VERSION 5.8 ;
DIVIDERCHAR "/" ;
BUSBITCHARS "[]" ;

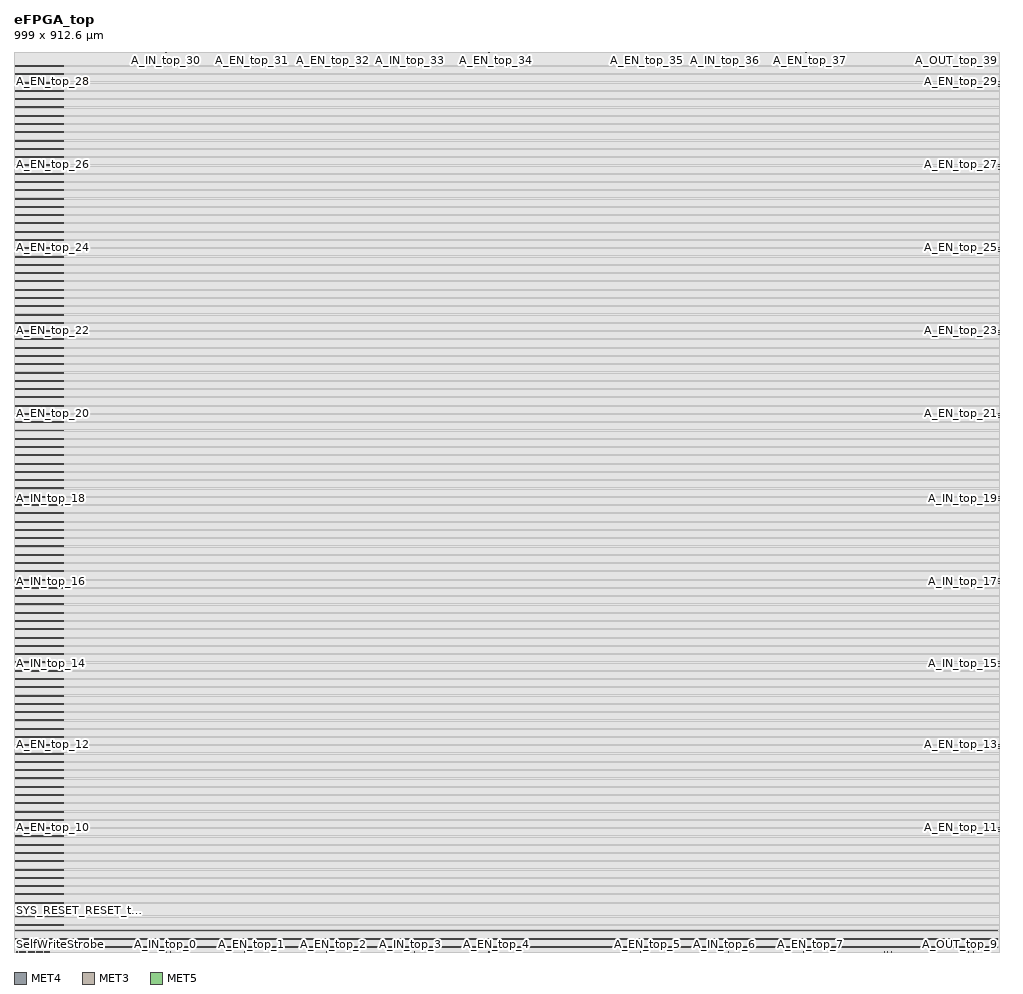
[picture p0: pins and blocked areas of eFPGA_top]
MACRO eFPGA_top
  CLASS BLOCK ;
  FOREIGN eFPGA_top ;
  ORIGIN 0.0 0.0 ;
  SIZE 999.000 BY 912.600 ;
  SYMMETRY X Y ;
  PIN CLK
    DIRECTION INPUT ;
    USE SIGNAL ;
    PORT
      LAYER MET4 ;
        RECT 2.450 0.000 2.550 0.550 ;
    END
  END CLK
  PIN A_EN_top_0
    DIRECTION OUTPUT ;
    USE SIGNAL ;
    PORT
      LAYER MET4 ;
        RECT 158.450 0.000 158.550 0.550 ;
    END
  END A_EN_top_0
  PIN A_EN_top_1
    DIRECTION OUTPUT ;
    USE SIGNAL ;
    PORT
      LAYER MET4 ;
        RECT 241.050 0.000 241.150 0.550 ;
    END
  END A_EN_top_1
  PIN A_EN_top_2
    DIRECTION OUTPUT ;
    USE SIGNAL ;
    PORT
      LAYER MET4 ;
        RECT 323.650 0.000 323.750 0.550 ;
    END
  END A_EN_top_2
  PIN A_EN_top_3
    DIRECTION OUTPUT ;
    USE SIGNAL ;
    PORT
      LAYER MET4 ;
        RECT 406.250 0.000 406.350 0.550 ;
    END
  END A_EN_top_3
  PIN A_EN_top_4
    DIRECTION OUTPUT ;
    USE SIGNAL ;
    PORT
      LAYER MET4 ;
        RECT 488.850 0.000 488.950 0.550 ;
    END
  END A_EN_top_4
  PIN A_EN_top_5
    DIRECTION OUTPUT ;
    USE SIGNAL ;
    PORT
      LAYER MET4 ;
        RECT 642.250 0.000 642.350 0.550 ;
    END
  END A_EN_top_5
  PIN A_EN_top_6
    DIRECTION OUTPUT ;
    USE SIGNAL ;
    PORT
      LAYER MET4 ;
        RECT 724.850 0.000 724.950 0.550 ;
    END
  END A_EN_top_6
  PIN A_EN_top_7
    DIRECTION OUTPUT ;
    USE SIGNAL ;
    PORT
      LAYER MET4 ;
        RECT 807.450 0.000 807.550 0.550 ;
    END
  END A_EN_top_7
  PIN A_EN_top_8
    DIRECTION OUTPUT ;
    USE SIGNAL ;
    PORT
      LAYER MET4 ;
        RECT 890.050 0.000 890.150 0.550 ;
    END
  END A_EN_top_8
  PIN A_EN_top_9
    DIRECTION OUTPUT ;
    USE SIGNAL ;
    PORT
      LAYER MET4 ;
        RECT 972.650 0.000 972.750 0.550 ;
    END
  END A_EN_top_9
  PIN A_EN_top_10
    DIRECTION OUTPUT ;
    USE SIGNAL ;
    PORT
      LAYER MET3 ;
        RECT 0.000 126.250 0.550 126.350 ;
    END
  END A_EN_top_10
  PIN A_EN_top_11
    DIRECTION OUTPUT ;
    USE SIGNAL ;
    PORT
      LAYER MET3 ;
        RECT 998.450 126.250 999.000 126.350 ;
    END
  END A_EN_top_11
  PIN A_EN_top_12
    DIRECTION OUTPUT ;
    USE SIGNAL ;
    PORT
      LAYER MET3 ;
        RECT 0.000 210.250 0.550 210.350 ;
    END
  END A_EN_top_12
  PIN A_EN_top_13
    DIRECTION OUTPUT ;
    USE SIGNAL ;
    PORT
      LAYER MET3 ;
        RECT 998.450 210.250 999.000 210.350 ;
    END
  END A_EN_top_13
  PIN A_EN_top_14
    DIRECTION OUTPUT ;
    USE SIGNAL ;
    PORT
      LAYER MET3 ;
        RECT 0.000 294.250 0.550 294.350 ;
    END
  END A_EN_top_14
  PIN A_EN_top_15
    DIRECTION OUTPUT ;
    USE SIGNAL ;
    PORT
      LAYER MET3 ;
        RECT 998.450 294.250 999.000 294.350 ;
    END
  END A_EN_top_15
  PIN A_EN_top_16
    DIRECTION OUTPUT ;
    USE SIGNAL ;
    PORT
      LAYER MET3 ;
        RECT 0.000 378.250 0.550 378.350 ;
    END
  END A_EN_top_16
  PIN A_EN_top_17
    DIRECTION OUTPUT ;
    USE SIGNAL ;
    PORT
      LAYER MET3 ;
        RECT 998.450 378.250 999.000 378.350 ;
    END
  END A_EN_top_17
  PIN A_EN_top_18
    DIRECTION OUTPUT ;
    USE SIGNAL ;
    PORT
      LAYER MET3 ;
        RECT 0.000 462.250 0.550 462.350 ;
    END
  END A_EN_top_18
  PIN A_EN_top_19
    DIRECTION OUTPUT ;
    USE SIGNAL ;
    PORT
      LAYER MET3 ;
        RECT 998.450 462.250 999.000 462.350 ;
    END
  END A_EN_top_19
  PIN A_EN_top_20
    DIRECTION OUTPUT ;
    USE SIGNAL ;
    PORT
      LAYER MET3 ;
        RECT 0.000 546.250 0.550 546.350 ;
    END
  END A_EN_top_20
  PIN A_EN_top_21
    DIRECTION OUTPUT ;
    USE SIGNAL ;
    PORT
      LAYER MET3 ;
        RECT 998.450 546.250 999.000 546.350 ;
    END
  END A_EN_top_21
  PIN A_EN_top_22
    DIRECTION OUTPUT ;
    USE SIGNAL ;
    PORT
      LAYER MET3 ;
        RECT 0.000 630.250 0.550 630.350 ;
    END
  END A_EN_top_22
  PIN A_EN_top_23
    DIRECTION OUTPUT ;
    USE SIGNAL ;
    PORT
      LAYER MET3 ;
        RECT 998.450 630.250 999.000 630.350 ;
    END
  END A_EN_top_23
  PIN A_EN_top_24
    DIRECTION OUTPUT ;
    USE SIGNAL ;
    PORT
      LAYER MET3 ;
        RECT 0.000 714.250 0.550 714.350 ;
    END
  END A_EN_top_24
  PIN A_EN_top_25
    DIRECTION OUTPUT ;
    USE SIGNAL ;
    PORT
      LAYER MET3 ;
        RECT 998.450 714.250 999.000 714.350 ;
    END
  END A_EN_top_25
  PIN A_EN_top_26
    DIRECTION OUTPUT ;
    USE SIGNAL ;
    PORT
      LAYER MET3 ;
        RECT 0.000 798.250 0.550 798.350 ;
    END
  END A_EN_top_26
  PIN A_EN_top_27
    DIRECTION OUTPUT ;
    USE SIGNAL ;
    PORT
      LAYER MET3 ;
        RECT 998.450 798.250 999.000 798.350 ;
    END
  END A_EN_top_27
  PIN A_EN_top_28
    DIRECTION OUTPUT ;
    USE SIGNAL ;
    PORT
      LAYER MET3 ;
        RECT 0.000 882.250 0.550 882.350 ;
    END
  END A_EN_top_28
  PIN A_EN_top_29
    DIRECTION OUTPUT ;
    USE SIGNAL ;
    PORT
      LAYER MET3 ;
        RECT 998.450 882.250 999.000 882.350 ;
    END
  END A_EN_top_29
  PIN A_EN_top_30
    DIRECTION OUTPUT ;
    USE SIGNAL ;
    PORT
      LAYER MET4 ;
        RECT 158.450 912.050 158.550 912.600 ;
    END
  END A_EN_top_30
  PIN A_EN_top_31
    DIRECTION OUTPUT ;
    USE SIGNAL ;
    PORT
      LAYER MET4 ;
        RECT 241.050 912.050 241.150 912.600 ;
    END
  END A_EN_top_31
  PIN A_EN_top_32
    DIRECTION OUTPUT ;
    USE SIGNAL ;
    PORT
      LAYER MET4 ;
        RECT 323.650 912.050 323.750 912.600 ;
    END
  END A_EN_top_32
  PIN A_EN_top_33
    DIRECTION OUTPUT ;
    USE SIGNAL ;
    PORT
      LAYER MET4 ;
        RECT 406.250 912.050 406.350 912.600 ;
    END
  END A_EN_top_33
  PIN A_EN_top_34
    DIRECTION OUTPUT ;
    USE SIGNAL ;
    PORT
      LAYER MET4 ;
        RECT 488.850 912.050 488.950 912.600 ;
    END
  END A_EN_top_34
  PIN A_EN_top_35
    DIRECTION OUTPUT ;
    USE SIGNAL ;
    PORT
      LAYER MET4 ;
        RECT 642.250 912.050 642.350 912.600 ;
    END
  END A_EN_top_35
  PIN A_EN_top_36
    DIRECTION OUTPUT ;
    USE SIGNAL ;
    PORT
      LAYER MET4 ;
        RECT 724.850 912.050 724.950 912.600 ;
    END
  END A_EN_top_36
  PIN A_EN_top_37
    DIRECTION OUTPUT ;
    USE SIGNAL ;
    PORT
      LAYER MET4 ;
        RECT 807.450 912.050 807.550 912.600 ;
    END
  END A_EN_top_37
  PIN A_EN_top_38
    DIRECTION OUTPUT ;
    USE SIGNAL ;
    PORT
      LAYER MET4 ;
        RECT 890.050 912.050 890.150 912.600 ;
    END
  END A_EN_top_38
  PIN A_EN_top_39
    DIRECTION OUTPUT ;
    USE SIGNAL ;
    PORT
      LAYER MET4 ;
        RECT 972.650 912.050 972.750 912.600 ;
    END
  END A_EN_top_39
  PIN A_IN_top_0
    DIRECTION OUTPUT ;
    USE SIGNAL ;
    PORT
      LAYER MET4 ;
        RECT 154.050 0.000 154.150 0.550 ;
    END
  END A_IN_top_0
  PIN A_IN_top_1
    DIRECTION OUTPUT ;
    USE SIGNAL ;
    PORT
      LAYER MET4 ;
        RECT 236.650 0.000 236.750 0.550 ;
    END
  END A_IN_top_1
  PIN A_IN_top_2
    DIRECTION OUTPUT ;
    USE SIGNAL ;
    PORT
      LAYER MET4 ;
        RECT 319.250 0.000 319.350 0.550 ;
    END
  END A_IN_top_2
  PIN A_IN_top_3
    DIRECTION OUTPUT ;
    USE SIGNAL ;
    PORT
      LAYER MET4 ;
        RECT 401.850 0.000 401.950 0.550 ;
    END
  END A_IN_top_3
  PIN A_IN_top_4
    DIRECTION OUTPUT ;
    USE SIGNAL ;
    PORT
      LAYER MET4 ;
        RECT 484.450 0.000 484.550 0.550 ;
    END
  END A_IN_top_4
  PIN A_IN_top_5
    DIRECTION OUTPUT ;
    USE SIGNAL ;
    PORT
      LAYER MET4 ;
        RECT 637.850 0.000 637.950 0.550 ;
    END
  END A_IN_top_5
  PIN A_IN_top_6
    DIRECTION OUTPUT ;
    USE SIGNAL ;
    PORT
      LAYER MET4 ;
        RECT 720.450 0.000 720.550 0.550 ;
    END
  END A_IN_top_6
  PIN A_IN_top_7
    DIRECTION OUTPUT ;
    USE SIGNAL ;
    PORT
      LAYER MET4 ;
        RECT 803.050 0.000 803.150 0.550 ;
    END
  END A_IN_top_7
  PIN A_IN_top_8
    DIRECTION OUTPUT ;
    USE SIGNAL ;
    PORT
      LAYER MET4 ;
        RECT 885.650 0.000 885.750 0.550 ;
    END
  END A_IN_top_8
  PIN A_IN_top_9
    DIRECTION OUTPUT ;
    USE SIGNAL ;
    PORT
      LAYER MET4 ;
        RECT 968.250 0.000 968.350 0.550 ;
    END
  END A_IN_top_9
  PIN A_IN_top_10
    DIRECTION OUTPUT ;
    USE SIGNAL ;
    PORT
      LAYER MET3 ;
        RECT 0.000 124.050 0.550 124.150 ;
    END
  END A_IN_top_10
  PIN A_IN_top_11
    DIRECTION OUTPUT ;
    USE SIGNAL ;
    PORT
      LAYER MET3 ;
        RECT 998.450 124.050 999.000 124.150 ;
    END
  END A_IN_top_11
  PIN A_IN_top_12
    DIRECTION OUTPUT ;
    USE SIGNAL ;
    PORT
      LAYER MET3 ;
        RECT 0.000 208.050 0.550 208.150 ;
    END
  END A_IN_top_12
  PIN A_IN_top_13
    DIRECTION OUTPUT ;
    USE SIGNAL ;
    PORT
      LAYER MET3 ;
        RECT 998.450 208.050 999.000 208.150 ;
    END
  END A_IN_top_13
  PIN A_IN_top_14
    DIRECTION OUTPUT ;
    USE SIGNAL ;
    PORT
      LAYER MET3 ;
        RECT 0.000 292.050 0.550 292.150 ;
    END
  END A_IN_top_14
  PIN A_IN_top_15
    DIRECTION OUTPUT ;
    USE SIGNAL ;
    PORT
      LAYER MET3 ;
        RECT 998.450 292.050 999.000 292.150 ;
    END
  END A_IN_top_15
  PIN A_IN_top_16
    DIRECTION OUTPUT ;
    USE SIGNAL ;
    PORT
      LAYER MET3 ;
        RECT 0.000 376.050 0.550 376.150 ;
    END
  END A_IN_top_16
  PIN A_IN_top_17
    DIRECTION OUTPUT ;
    USE SIGNAL ;
    PORT
      LAYER MET3 ;
        RECT 998.450 376.050 999.000 376.150 ;
    END
  END A_IN_top_17
  PIN A_IN_top_18
    DIRECTION OUTPUT ;
    USE SIGNAL ;
    PORT
      LAYER MET3 ;
        RECT 0.000 460.050 0.550 460.150 ;
    END
  END A_IN_top_18
  PIN A_IN_top_19
    DIRECTION OUTPUT ;
    USE SIGNAL ;
    PORT
      LAYER MET3 ;
        RECT 998.450 460.050 999.000 460.150 ;
    END
  END A_IN_top_19
  PIN A_IN_top_20
    DIRECTION OUTPUT ;
    USE SIGNAL ;
    PORT
      LAYER MET3 ;
        RECT 0.000 544.050 0.550 544.150 ;
    END
  END A_IN_top_20
  PIN A_IN_top_21
    DIRECTION OUTPUT ;
    USE SIGNAL ;
    PORT
      LAYER MET3 ;
        RECT 998.450 544.050 999.000 544.150 ;
    END
  END A_IN_top_21
  PIN A_IN_top_22
    DIRECTION OUTPUT ;
    USE SIGNAL ;
    PORT
      LAYER MET3 ;
        RECT 0.000 628.050 0.550 628.150 ;
    END
  END A_IN_top_22
  PIN A_IN_top_23
    DIRECTION OUTPUT ;
    USE SIGNAL ;
    PORT
      LAYER MET3 ;
        RECT 998.450 628.050 999.000 628.150 ;
    END
  END A_IN_top_23
  PIN A_IN_top_24
    DIRECTION OUTPUT ;
    USE SIGNAL ;
    PORT
      LAYER MET3 ;
        RECT 0.000 712.050 0.550 712.150 ;
    END
  END A_IN_top_24
  PIN A_IN_top_25
    DIRECTION OUTPUT ;
    USE SIGNAL ;
    PORT
      LAYER MET3 ;
        RECT 998.450 712.050 999.000 712.150 ;
    END
  END A_IN_top_25
  PIN A_IN_top_26
    DIRECTION OUTPUT ;
    USE SIGNAL ;
    PORT
      LAYER MET3 ;
        RECT 0.000 796.050 0.550 796.150 ;
    END
  END A_IN_top_26
  PIN A_IN_top_27
    DIRECTION OUTPUT ;
    USE SIGNAL ;
    PORT
      LAYER MET3 ;
        RECT 998.450 796.050 999.000 796.150 ;
    END
  END A_IN_top_27
  PIN A_IN_top_28
    DIRECTION OUTPUT ;
    USE SIGNAL ;
    PORT
      LAYER MET3 ;
        RECT 0.000 880.050 0.550 880.150 ;
    END
  END A_IN_top_28
  PIN A_IN_top_29
    DIRECTION OUTPUT ;
    USE SIGNAL ;
    PORT
      LAYER MET3 ;
        RECT 998.450 880.050 999.000 880.150 ;
    END
  END A_IN_top_29
  PIN A_IN_top_30
    DIRECTION OUTPUT ;
    USE SIGNAL ;
    PORT
      LAYER MET4 ;
        RECT 154.050 912.050 154.150 912.600 ;
    END
  END A_IN_top_30
  PIN A_IN_top_31
    DIRECTION OUTPUT ;
    USE SIGNAL ;
    PORT
      LAYER MET4 ;
        RECT 236.650 912.050 236.750 912.600 ;
    END
  END A_IN_top_31
  PIN A_IN_top_32
    DIRECTION OUTPUT ;
    USE SIGNAL ;
    PORT
      LAYER MET4 ;
        RECT 319.250 912.050 319.350 912.600 ;
    END
  END A_IN_top_32
  PIN A_IN_top_33
    DIRECTION OUTPUT ;
    USE SIGNAL ;
    PORT
      LAYER MET4 ;
        RECT 401.850 912.050 401.950 912.600 ;
    END
  END A_IN_top_33
  PIN A_IN_top_34
    DIRECTION OUTPUT ;
    USE SIGNAL ;
    PORT
      LAYER MET4 ;
        RECT 484.450 912.050 484.550 912.600 ;
    END
  END A_IN_top_34
  PIN A_IN_top_35
    DIRECTION OUTPUT ;
    USE SIGNAL ;
    PORT
      LAYER MET4 ;
        RECT 637.850 912.050 637.950 912.600 ;
    END
  END A_IN_top_35
  PIN A_IN_top_36
    DIRECTION OUTPUT ;
    USE SIGNAL ;
    PORT
      LAYER MET4 ;
        RECT 720.450 912.050 720.550 912.600 ;
    END
  END A_IN_top_36
  PIN A_IN_top_37
    DIRECTION OUTPUT ;
    USE SIGNAL ;
    PORT
      LAYER MET4 ;
        RECT 803.050 912.050 803.150 912.600 ;
    END
  END A_IN_top_37
  PIN A_IN_top_38
    DIRECTION OUTPUT ;
    USE SIGNAL ;
    PORT
      LAYER MET4 ;
        RECT 885.650 912.050 885.750 912.600 ;
    END
  END A_IN_top_38
  PIN A_IN_top_39
    DIRECTION OUTPUT ;
    USE SIGNAL ;
    PORT
      LAYER MET4 ;
        RECT 968.250 912.050 968.350 912.600 ;
    END
  END A_IN_top_39
  PIN A_OUT_top_0
    DIRECTION INPUT ;
    USE SIGNAL ;
    PORT
      LAYER MET4 ;
        RECT 151.250 0.000 151.350 0.550 ;
    END
  END A_OUT_top_0
  PIN A_OUT_top_1
    DIRECTION INPUT ;
    USE SIGNAL ;
    PORT
      LAYER MET4 ;
        RECT 233.850 0.000 233.950 0.550 ;
    END
  END A_OUT_top_1
  PIN A_OUT_top_2
    DIRECTION INPUT ;
    USE SIGNAL ;
    PORT
      LAYER MET4 ;
        RECT 316.450 0.000 316.550 0.550 ;
    END
  END A_OUT_top_2
  PIN A_OUT_top_3
    DIRECTION INPUT ;
    USE SIGNAL ;
    PORT
      LAYER MET4 ;
        RECT 399.050 0.000 399.150 0.550 ;
    END
  END A_OUT_top_3
  PIN A_OUT_top_4
    DIRECTION INPUT ;
    USE SIGNAL ;
    PORT
      LAYER MET4 ;
        RECT 481.650 0.000 481.750 0.550 ;
    END
  END A_OUT_top_4
  PIN A_OUT_top_5
    DIRECTION INPUT ;
    USE SIGNAL ;
    PORT
      LAYER MET4 ;
        RECT 635.050 0.000 635.150 0.550 ;
    END
  END A_OUT_top_5
  PIN A_OUT_top_6
    DIRECTION INPUT ;
    USE SIGNAL ;
    PORT
      LAYER MET4 ;
        RECT 717.650 0.000 717.750 0.550 ;
    END
  END A_OUT_top_6
  PIN A_OUT_top_7
    DIRECTION INPUT ;
    USE SIGNAL ;
    PORT
      LAYER MET4 ;
        RECT 800.250 0.000 800.350 0.550 ;
    END
  END A_OUT_top_7
  PIN A_OUT_top_8
    DIRECTION INPUT ;
    USE SIGNAL ;
    PORT
      LAYER MET4 ;
        RECT 882.850 0.000 882.950 0.550 ;
    END
  END A_OUT_top_8
  PIN A_OUT_top_9
    DIRECTION INPUT ;
    USE SIGNAL ;
    PORT
      LAYER MET4 ;
        RECT 965.450 0.000 965.550 0.550 ;
    END
  END A_OUT_top_9
  PIN A_OUT_top_10
    DIRECTION INPUT ;
    USE SIGNAL ;
    PORT
      LAYER MET3 ;
        RECT 0.000 121.850 0.550 121.950 ;
    END
  END A_OUT_top_10
  PIN A_OUT_top_11
    DIRECTION INPUT ;
    USE SIGNAL ;
    PORT
      LAYER MET3 ;
        RECT 998.450 121.850 999.000 121.950 ;
    END
  END A_OUT_top_11
  PIN A_OUT_top_12
    DIRECTION INPUT ;
    USE SIGNAL ;
    PORT
      LAYER MET3 ;
        RECT 0.000 205.850 0.550 205.950 ;
    END
  END A_OUT_top_12
  PIN A_OUT_top_13
    DIRECTION INPUT ;
    USE SIGNAL ;
    PORT
      LAYER MET3 ;
        RECT 998.450 205.850 999.000 205.950 ;
    END
  END A_OUT_top_13
  PIN A_OUT_top_14
    DIRECTION INPUT ;
    USE SIGNAL ;
    PORT
      LAYER MET3 ;
        RECT 0.000 289.850 0.550 289.950 ;
    END
  END A_OUT_top_14
  PIN A_OUT_top_15
    DIRECTION INPUT ;
    USE SIGNAL ;
    PORT
      LAYER MET3 ;
        RECT 998.450 289.850 999.000 289.950 ;
    END
  END A_OUT_top_15
  PIN A_OUT_top_16
    DIRECTION INPUT ;
    USE SIGNAL ;
    PORT
      LAYER MET3 ;
        RECT 0.000 373.850 0.550 373.950 ;
    END
  END A_OUT_top_16
  PIN A_OUT_top_17
    DIRECTION INPUT ;
    USE SIGNAL ;
    PORT
      LAYER MET3 ;
        RECT 998.450 373.850 999.000 373.950 ;
    END
  END A_OUT_top_17
  PIN A_OUT_top_18
    DIRECTION INPUT ;
    USE SIGNAL ;
    PORT
      LAYER MET3 ;
        RECT 0.000 457.850 0.550 457.950 ;
    END
  END A_OUT_top_18
  PIN A_OUT_top_19
    DIRECTION INPUT ;
    USE SIGNAL ;
    PORT
      LAYER MET3 ;
        RECT 998.450 457.850 999.000 457.950 ;
    END
  END A_OUT_top_19
  PIN A_OUT_top_20
    DIRECTION INPUT ;
    USE SIGNAL ;
    PORT
      LAYER MET3 ;
        RECT 0.000 541.850 0.550 541.950 ;
    END
  END A_OUT_top_20
  PIN A_OUT_top_21
    DIRECTION INPUT ;
    USE SIGNAL ;
    PORT
      LAYER MET3 ;
        RECT 998.450 541.850 999.000 541.950 ;
    END
  END A_OUT_top_21
  PIN A_OUT_top_22
    DIRECTION INPUT ;
    USE SIGNAL ;
    PORT
      LAYER MET3 ;
        RECT 0.000 625.850 0.550 625.950 ;
    END
  END A_OUT_top_22
  PIN A_OUT_top_23
    DIRECTION INPUT ;
    USE SIGNAL ;
    PORT
      LAYER MET3 ;
        RECT 998.450 625.850 999.000 625.950 ;
    END
  END A_OUT_top_23
  PIN A_OUT_top_24
    DIRECTION INPUT ;
    USE SIGNAL ;
    PORT
      LAYER MET3 ;
        RECT 0.000 709.850 0.550 709.950 ;
    END
  END A_OUT_top_24
  PIN A_OUT_top_25
    DIRECTION INPUT ;
    USE SIGNAL ;
    PORT
      LAYER MET3 ;
        RECT 998.450 709.850 999.000 709.950 ;
    END
  END A_OUT_top_25
  PIN A_OUT_top_26
    DIRECTION INPUT ;
    USE SIGNAL ;
    PORT
      LAYER MET3 ;
        RECT 0.000 793.850 0.550 793.950 ;
    END
  END A_OUT_top_26
  PIN A_OUT_top_27
    DIRECTION INPUT ;
    USE SIGNAL ;
    PORT
      LAYER MET3 ;
        RECT 998.450 793.850 999.000 793.950 ;
    END
  END A_OUT_top_27
  PIN A_OUT_top_28
    DIRECTION INPUT ;
    USE SIGNAL ;
    PORT
      LAYER MET3 ;
        RECT 0.000 877.850 0.550 877.950 ;
    END
  END A_OUT_top_28
  PIN A_OUT_top_29
    DIRECTION INPUT ;
    USE SIGNAL ;
    PORT
      LAYER MET3 ;
        RECT 998.450 877.850 999.000 877.950 ;
    END
  END A_OUT_top_29
  PIN A_OUT_top_30
    DIRECTION INPUT ;
    USE SIGNAL ;
    PORT
      LAYER MET4 ;
        RECT 151.250 912.050 151.350 912.600 ;
    END
  END A_OUT_top_30
  PIN A_OUT_top_31
    DIRECTION INPUT ;
    USE SIGNAL ;
    PORT
      LAYER MET4 ;
        RECT 233.850 912.050 233.950 912.600 ;
    END
  END A_OUT_top_31
  PIN A_OUT_top_32
    DIRECTION INPUT ;
    USE SIGNAL ;
    PORT
      LAYER MET4 ;
        RECT 316.450 912.050 316.550 912.600 ;
    END
  END A_OUT_top_32
  PIN A_OUT_top_33
    DIRECTION INPUT ;
    USE SIGNAL ;
    PORT
      LAYER MET4 ;
        RECT 399.050 912.050 399.150 912.600 ;
    END
  END A_OUT_top_33
  PIN A_OUT_top_34
    DIRECTION INPUT ;
    USE SIGNAL ;
    PORT
      LAYER MET4 ;
        RECT 481.650 912.050 481.750 912.600 ;
    END
  END A_OUT_top_34
  PIN A_OUT_top_35
    DIRECTION INPUT ;
    USE SIGNAL ;
    PORT
      LAYER MET4 ;
        RECT 635.050 912.050 635.150 912.600 ;
    END
  END A_OUT_top_35
  PIN A_OUT_top_36
    DIRECTION INPUT ;
    USE SIGNAL ;
    PORT
      LAYER MET4 ;
        RECT 717.650 912.050 717.750 912.600 ;
    END
  END A_OUT_top_36
  PIN A_OUT_top_37
    DIRECTION INPUT ;
    USE SIGNAL ;
    PORT
      LAYER MET4 ;
        RECT 800.250 912.050 800.350 912.600 ;
    END
  END A_OUT_top_37
  PIN A_OUT_top_38
    DIRECTION INPUT ;
    USE SIGNAL ;
    PORT
      LAYER MET4 ;
        RECT 882.850 912.050 882.950 912.600 ;
    END
  END A_OUT_top_38
  PIN A_OUT_top_39
    DIRECTION INPUT ;
    USE SIGNAL ;
    PORT
      LAYER MET4 ;
        RECT 965.450 912.050 965.550 912.600 ;
    END
  END A_OUT_top_39
  PIN SYS_RESET_RESET_top
    DIRECTION INPUT ;
    USE SIGNAL ;
    PORT
      LAYER MET3 ;
        RECT 0.000 42.050 0.550 42.150 ;
    END
  END SYS_RESET_RESET_top
  PIN resetn
    DIRECTION INPUT ;
    USE SIGNAL ;
    PORT
      LAYER MET4 ;
        RECT 33.050 0.000 33.150 0.550 ;
    END
  END resetn
  PIN Rx
    DIRECTION INPUT ;
    USE SIGNAL ;
    PORT
      LAYER MET4 ;
        RECT 7.250 0.000 7.350 0.550 ;
    END
  END Rx
  PIN ComActive
    DIRECTION OUTPUT ;
    USE SIGNAL ;
    PORT
      LAYER MET4 ;
        RECT 3.050 0.000 3.150 0.550 ;
    END
  END ComActive
  PIN ReceiveLED
    DIRECTION OUTPUT ;
    USE SIGNAL ;
    PORT
      LAYER MET4 ;
        RECT 6.650 0.000 6.750 0.550 ;
    END
  END ReceiveLED
  PIN s_clk
    DIRECTION INPUT ;
    USE SIGNAL ;
    PORT
      LAYER MET4 ;
        RECT 33.650 0.000 33.750 0.550 ;
    END
  END s_clk
  PIN s_data
    DIRECTION INPUT ;
    USE SIGNAL ;
    PORT
      LAYER MET4 ;
        RECT 34.250 0.000 34.350 0.550 ;
    END
  END s_data
  PIN spi_sck
    DIRECTION INPUT ;
    USE SIGNAL ;
    PORT
      LAYER MET4 ;
        RECT 36.050 0.000 36.150 0.550 ;
    END
  END spi_sck
  PIN spi_cs_n
    DIRECTION INPUT ;
    USE SIGNAL ;
    PORT
      LAYER MET4 ;
        RECT 34.850 0.000 34.950 0.550 ;
    END
  END spi_cs_n
  PIN spi_mosi
    DIRECTION INPUT ;
    USE SIGNAL ;
    PORT
      LAYER MET4 ;
        RECT 35.450 0.000 35.550 0.550 ;
    END
  END spi_mosi
  PIN SelfWriteData_0
    DIRECTION INPUT ;
    USE SIGNAL ;
    PORT
      LAYER MET4 ;
        RECT 7.850 0.000 7.950 0.550 ;
    END
  END SelfWriteData_0
  PIN SelfWriteData_1
    DIRECTION INPUT ;
    USE SIGNAL ;
    PORT
      LAYER MET4 ;
        RECT 8.450 0.000 8.550 0.550 ;
    END
  END SelfWriteData_1
  PIN SelfWriteData_2
    DIRECTION INPUT ;
    USE SIGNAL ;
    PORT
      LAYER MET4 ;
        RECT 16.850 0.000 16.950 0.550 ;
    END
  END SelfWriteData_2
  PIN SelfWriteData_3
    DIRECTION INPUT ;
    USE SIGNAL ;
    PORT
      LAYER MET4 ;
        RECT 25.250 0.000 25.350 0.550 ;
    END
  END SelfWriteData_3
  PIN SelfWriteData_4
    DIRECTION INPUT ;
    USE SIGNAL ;
    PORT
      LAYER MET4 ;
        RECT 27.050 0.000 27.150 0.550 ;
    END
  END SelfWriteData_4
  PIN SelfWriteData_5
    DIRECTION INPUT ;
    USE SIGNAL ;
    PORT
      LAYER MET4 ;
        RECT 27.650 0.000 27.750 0.550 ;
    END
  END SelfWriteData_5
  PIN SelfWriteData_6
    DIRECTION INPUT ;
    USE SIGNAL ;
    PORT
      LAYER MET4 ;
        RECT 28.250 0.000 28.350 0.550 ;
    END
  END SelfWriteData_6
  PIN SelfWriteData_7
    DIRECTION INPUT ;
    USE SIGNAL ;
    PORT
      LAYER MET4 ;
        RECT 28.850 0.000 28.950 0.550 ;
    END
  END SelfWriteData_7
  PIN SelfWriteData_8
    DIRECTION INPUT ;
    USE SIGNAL ;
    PORT
      LAYER MET4 ;
        RECT 31.250 0.000 31.350 0.550 ;
    END
  END SelfWriteData_8
  PIN SelfWriteData_9
    DIRECTION INPUT ;
    USE SIGNAL ;
    PORT
      LAYER MET4 ;
        RECT 31.850 0.000 31.950 0.550 ;
    END
  END SelfWriteData_9
  PIN SelfWriteData_10
    DIRECTION INPUT ;
    USE SIGNAL ;
    PORT
      LAYER MET4 ;
        RECT 9.050 0.000 9.150 0.550 ;
    END
  END SelfWriteData_10
  PIN SelfWriteData_11
    DIRECTION INPUT ;
    USE SIGNAL ;
    PORT
      LAYER MET4 ;
        RECT 9.650 0.000 9.750 0.550 ;
    END
  END SelfWriteData_11
  PIN SelfWriteData_12
    DIRECTION INPUT ;
    USE SIGNAL ;
    PORT
      LAYER MET4 ;
        RECT 10.250 0.000 10.350 0.550 ;
    END
  END SelfWriteData_12
  PIN SelfWriteData_13
    DIRECTION INPUT ;
    USE SIGNAL ;
    PORT
      LAYER MET4 ;
        RECT 10.850 0.000 10.950 0.550 ;
    END
  END SelfWriteData_13
  PIN SelfWriteData_14
    DIRECTION INPUT ;
    USE SIGNAL ;
    PORT
      LAYER MET4 ;
        RECT 11.450 0.000 11.550 0.550 ;
    END
  END SelfWriteData_14
  PIN SelfWriteData_15
    DIRECTION INPUT ;
    USE SIGNAL ;
    PORT
      LAYER MET4 ;
        RECT 12.050 0.000 12.150 0.550 ;
    END
  END SelfWriteData_15
  PIN SelfWriteData_16
    DIRECTION INPUT ;
    USE SIGNAL ;
    PORT
      LAYER MET4 ;
        RECT 14.450 0.000 14.550 0.550 ;
    END
  END SelfWriteData_16
  PIN SelfWriteData_17
    DIRECTION INPUT ;
    USE SIGNAL ;
    PORT
      LAYER MET4 ;
        RECT 15.050 0.000 15.150 0.550 ;
    END
  END SelfWriteData_17
  PIN SelfWriteData_18
    DIRECTION INPUT ;
    USE SIGNAL ;
    PORT
      LAYER MET4 ;
        RECT 15.650 0.000 15.750 0.550 ;
    END
  END SelfWriteData_18
  PIN SelfWriteData_19
    DIRECTION INPUT ;
    USE SIGNAL ;
    PORT
      LAYER MET4 ;
        RECT 16.250 0.000 16.350 0.550 ;
    END
  END SelfWriteData_19
  PIN SelfWriteData_20
    DIRECTION INPUT ;
    USE SIGNAL ;
    PORT
      LAYER MET4 ;
        RECT 17.450 0.000 17.550 0.550 ;
    END
  END SelfWriteData_20
  PIN SelfWriteData_21
    DIRECTION INPUT ;
    USE SIGNAL ;
    PORT
      LAYER MET4 ;
        RECT 18.050 0.000 18.150 0.550 ;
    END
  END SelfWriteData_21
  PIN SelfWriteData_22
    DIRECTION INPUT ;
    USE SIGNAL ;
    PORT
      LAYER MET4 ;
        RECT 18.650 0.000 18.750 0.550 ;
    END
  END SelfWriteData_22
  PIN SelfWriteData_23
    DIRECTION INPUT ;
    USE SIGNAL ;
    PORT
      LAYER MET4 ;
        RECT 19.250 0.000 19.350 0.550 ;
    END
  END SelfWriteData_23
  PIN SelfWriteData_24
    DIRECTION INPUT ;
    USE SIGNAL ;
    PORT
      LAYER MET4 ;
        RECT 19.850 0.000 19.950 0.550 ;
    END
  END SelfWriteData_24
  PIN SelfWriteData_25
    DIRECTION INPUT ;
    USE SIGNAL ;
    PORT
      LAYER MET4 ;
        RECT 20.450 0.000 20.550 0.550 ;
    END
  END SelfWriteData_25
  PIN SelfWriteData_26
    DIRECTION INPUT ;
    USE SIGNAL ;
    PORT
      LAYER MET4 ;
        RECT 22.850 0.000 22.950 0.550 ;
    END
  END SelfWriteData_26
  PIN SelfWriteData_27
    DIRECTION INPUT ;
    USE SIGNAL ;
    PORT
      LAYER MET4 ;
        RECT 23.450 0.000 23.550 0.550 ;
    END
  END SelfWriteData_27
  PIN SelfWriteData_28
    DIRECTION INPUT ;
    USE SIGNAL ;
    PORT
      LAYER MET4 ;
        RECT 24.050 0.000 24.150 0.550 ;
    END
  END SelfWriteData_28
  PIN SelfWriteData_29
    DIRECTION INPUT ;
    USE SIGNAL ;
    PORT
      LAYER MET4 ;
        RECT 24.650 0.000 24.750 0.550 ;
    END
  END SelfWriteData_29
  PIN SelfWriteData_30
    DIRECTION INPUT ;
    USE SIGNAL ;
    PORT
      LAYER MET4 ;
        RECT 25.850 0.000 25.950 0.550 ;
    END
  END SelfWriteData_30
  PIN SelfWriteData_31
    DIRECTION INPUT ;
    USE SIGNAL ;
    PORT
      LAYER MET4 ;
        RECT 26.450 0.000 26.550 0.550 ;
    END
  END SelfWriteData_31
  PIN SelfWriteStrobe
    DIRECTION INPUT ;
    USE SIGNAL ;
    PORT
      LAYER MET4 ;
        RECT 32.450 0.000 32.550 0.550 ;
    END
  END SelfWriteStrobe
  PIN ConfigBusy
    DIRECTION OUTPUT ;
    USE SIGNAL ;
    PORT
      LAYER MET4 ;
        RECT 3.650 0.000 3.750 0.550 ;
    END
  END ConfigBusy
  PIN Configured
    DIRECTION OUTPUT ;
    USE SIGNAL ;
    PORT
      LAYER MET4 ;
        RECT 6.050 0.000 6.150 0.550 ;
    END
  END Configured
  PIN vdd_stripe_generate
    DIRECTION INOUT ;
    USE POWER ;
    PORT
      LAYER MET5 ;
        RECT 2.000 889.500 50.000 890.500 ;
      LAYER MET5 ;
        RECT 2.000 805.500 50.000 806.500 ;
      LAYER MET5 ;
        RECT 2.000 822.300 50.000 823.300 ;
      LAYER MET5 ;
        RECT 2.000 839.100 50.000 840.100 ;
      LAYER MET5 ;
        RECT 2.000 855.900 50.000 856.900 ;
      LAYER MET5 ;
        RECT 2.000 872.700 50.000 873.700 ;
      LAYER MET5 ;
        RECT 2.000 721.500 50.000 722.500 ;
      LAYER MET5 ;
        RECT 2.000 738.300 50.000 739.300 ;
      LAYER MET5 ;
        RECT 2.000 755.100 50.000 756.100 ;
      LAYER MET5 ;
        RECT 2.000 771.900 50.000 772.900 ;
      LAYER MET5 ;
        RECT 2.000 788.700 50.000 789.700 ;
      LAYER MET5 ;
        RECT 2.000 637.500 50.000 638.500 ;
      LAYER MET5 ;
        RECT 2.000 654.300 50.000 655.300 ;
      LAYER MET5 ;
        RECT 2.000 671.100 50.000 672.100 ;
      LAYER MET5 ;
        RECT 2.000 687.900 50.000 688.900 ;
      LAYER MET5 ;
        RECT 2.000 704.700 50.000 705.700 ;
      LAYER MET5 ;
        RECT 2.000 553.500 50.000 554.500 ;
      LAYER MET5 ;
        RECT 2.000 570.300 50.000 571.300 ;
      LAYER MET5 ;
        RECT 2.000 587.100 50.000 588.100 ;
      LAYER MET5 ;
        RECT 2.000 603.900 50.000 604.900 ;
      LAYER MET5 ;
        RECT 2.000 620.700 50.000 621.700 ;
      LAYER MET5 ;
        RECT 2.000 469.500 50.000 470.500 ;
      LAYER MET5 ;
        RECT 2.000 486.300 50.000 487.300 ;
      LAYER MET5 ;
        RECT 2.000 503.100 50.000 504.100 ;
      LAYER MET5 ;
        RECT 2.000 519.900 50.000 520.900 ;
      LAYER MET5 ;
        RECT 2.000 536.700 50.000 537.700 ;
      LAYER MET5 ;
        RECT 2.000 385.500 50.000 386.500 ;
      LAYER MET5 ;
        RECT 2.000 402.300 50.000 403.300 ;
      LAYER MET5 ;
        RECT 2.000 419.100 50.000 420.100 ;
      LAYER MET5 ;
        RECT 2.000 435.900 50.000 436.900 ;
      LAYER MET5 ;
        RECT 2.000 452.700 50.000 453.700 ;
      LAYER MET5 ;
        RECT 2.000 301.500 50.000 302.500 ;
      LAYER MET5 ;
        RECT 2.000 318.300 50.000 319.300 ;
      LAYER MET5 ;
        RECT 2.000 335.100 50.000 336.100 ;
      LAYER MET5 ;
        RECT 2.000 351.900 50.000 352.900 ;
      LAYER MET5 ;
        RECT 2.000 368.700 50.000 369.700 ;
      LAYER MET5 ;
        RECT 2.000 217.500 50.000 218.500 ;
      LAYER MET5 ;
        RECT 2.000 234.300 50.000 235.300 ;
      LAYER MET5 ;
        RECT 2.000 251.100 50.000 252.100 ;
      LAYER MET5 ;
        RECT 2.000 267.900 50.000 268.900 ;
      LAYER MET5 ;
        RECT 2.000 284.700 50.000 285.700 ;
      LAYER MET5 ;
        RECT 2.000 133.500 50.000 134.500 ;
      LAYER MET5 ;
        RECT 2.000 150.300 50.000 151.300 ;
      LAYER MET5 ;
        RECT 2.000 167.100 50.000 168.100 ;
      LAYER MET5 ;
        RECT 2.000 183.900 50.000 184.900 ;
      LAYER MET5 ;
        RECT 2.000 200.700 50.000 201.700 ;
      LAYER MET5 ;
        RECT 2.000 49.500 50.000 50.500 ;
      LAYER MET5 ;
        RECT 2.000 66.300 50.000 67.300 ;
      LAYER MET5 ;
        RECT 2.000 83.100 50.000 84.100 ;
      LAYER MET5 ;
        RECT 2.000 99.900 50.000 100.900 ;
      LAYER MET5 ;
        RECT 2.000 116.700 50.000 117.700 ;
      LAYER MET5 ;
        RECT 2.000 27.100 50.000 28.100 ;
      LAYER MET5 ;
        RECT 2.000 4.500 997.000 5.500 ;
      LAYER MET5 ;
        RECT 2.000 21.300 997.000 22.300 ;
    END
  END vdd_stripe_generate
  PIN vss_stripe_generate
    DIRECTION INOUT ;
    USE GROUND ;
    PORT
      LAYER MET5 ;
        RECT 2.000 897.900 50.000 898.900 ;
      LAYER MET5 ;
        RECT 2.000 813.900 50.000 814.900 ;
      LAYER MET5 ;
        RECT 2.000 830.700 50.000 831.700 ;
      LAYER MET5 ;
        RECT 2.000 847.500 50.000 848.500 ;
      LAYER MET5 ;
        RECT 2.000 864.300 50.000 865.300 ;
      LAYER MET5 ;
        RECT 2.000 881.100 50.000 882.100 ;
      LAYER MET5 ;
        RECT 2.000 729.900 50.000 730.900 ;
      LAYER MET5 ;
        RECT 2.000 746.700 50.000 747.700 ;
      LAYER MET5 ;
        RECT 2.000 763.500 50.000 764.500 ;
      LAYER MET5 ;
        RECT 2.000 780.300 50.000 781.300 ;
      LAYER MET5 ;
        RECT 2.000 797.100 50.000 798.100 ;
      LAYER MET5 ;
        RECT 2.000 645.900 50.000 646.900 ;
      LAYER MET5 ;
        RECT 2.000 662.700 50.000 663.700 ;
      LAYER MET5 ;
        RECT 2.000 679.500 50.000 680.500 ;
      LAYER MET5 ;
        RECT 2.000 696.300 50.000 697.300 ;
      LAYER MET5 ;
        RECT 2.000 713.100 50.000 714.100 ;
      LAYER MET5 ;
        RECT 2.000 561.900 50.000 562.900 ;
      LAYER MET5 ;
        RECT 2.000 578.700 50.000 579.700 ;
      LAYER MET5 ;
        RECT 2.000 595.500 50.000 596.500 ;
      LAYER MET5 ;
        RECT 2.000 612.300 50.000 613.300 ;
      LAYER MET5 ;
        RECT 2.000 629.100 50.000 630.100 ;
      LAYER MET5 ;
        RECT 2.000 477.900 50.000 478.900 ;
      LAYER MET5 ;
        RECT 2.000 494.700 50.000 495.700 ;
      LAYER MET5 ;
        RECT 2.000 511.500 50.000 512.500 ;
      LAYER MET5 ;
        RECT 2.000 528.300 50.000 529.300 ;
      LAYER MET5 ;
        RECT 2.000 545.100 50.000 546.100 ;
      LAYER MET5 ;
        RECT 2.000 393.900 50.000 394.900 ;
      LAYER MET5 ;
        RECT 2.000 410.700 50.000 411.700 ;
      LAYER MET5 ;
        RECT 2.000 427.500 50.000 428.500 ;
      LAYER MET5 ;
        RECT 2.000 444.300 50.000 445.300 ;
      LAYER MET5 ;
        RECT 2.000 461.100 50.000 462.100 ;
      LAYER MET5 ;
        RECT 2.000 309.900 50.000 310.900 ;
      LAYER MET5 ;
        RECT 2.000 326.700 50.000 327.700 ;
      LAYER MET5 ;
        RECT 2.000 343.500 50.000 344.500 ;
      LAYER MET5 ;
        RECT 2.000 360.300 50.000 361.300 ;
      LAYER MET5 ;
        RECT 2.000 377.100 50.000 378.100 ;
      LAYER MET5 ;
        RECT 2.000 225.900 50.000 226.900 ;
      LAYER MET5 ;
        RECT 2.000 242.700 50.000 243.700 ;
      LAYER MET5 ;
        RECT 2.000 259.500 50.000 260.500 ;
      LAYER MET5 ;
        RECT 2.000 276.300 50.000 277.300 ;
      LAYER MET5 ;
        RECT 2.000 293.100 50.000 294.100 ;
      LAYER MET5 ;
        RECT 2.000 141.900 50.000 142.900 ;
      LAYER MET5 ;
        RECT 2.000 158.700 50.000 159.700 ;
      LAYER MET5 ;
        RECT 2.000 175.500 50.000 176.500 ;
      LAYER MET5 ;
        RECT 2.000 192.300 50.000 193.300 ;
      LAYER MET5 ;
        RECT 2.000 209.100 50.000 210.100 ;
      LAYER MET5 ;
        RECT 2.000 57.900 50.000 58.900 ;
      LAYER MET5 ;
        RECT 2.000 74.700 50.000 75.700 ;
      LAYER MET5 ;
        RECT 2.000 91.500 50.000 92.500 ;
      LAYER MET5 ;
        RECT 2.000 108.300 50.000 109.300 ;
      LAYER MET5 ;
        RECT 2.000 125.100 50.000 126.100 ;
      LAYER MET5 ;
        RECT 2.000 35.500 50.000 36.500 ;
      LAYER MET5 ;
        RECT 2.000 12.900 997.000 13.900 ;
    END
  END vss_stripe_generate
  OBS
    LAYER MET1 ;
    RECT 0.000 0.000 999.000 912.600 ;
    LAYER MET2 ;
    RECT 0.000 0.000 999.000 912.600 ;
    LAYER MET3 ;
    RECT 0.000 0.000 999.000 41.950 ;
    LAYER MET3 ;
    RECT 0.650 41.950 999.000 42.250 ;
    LAYER MET3 ;
    RECT 0.000 42.250 999.000 121.750 ;
    LAYER MET3 ;
    RECT 0.650 121.750 998.350 122.050 ;
    LAYER MET3 ;
    RECT 0.000 122.050 999.000 123.950 ;
    LAYER MET3 ;
    RECT 0.650 123.950 998.350 124.250 ;
    LAYER MET3 ;
    RECT 0.000 124.250 999.000 126.150 ;
    LAYER MET3 ;
    RECT 0.650 126.150 998.350 126.450 ;
    LAYER MET3 ;
    RECT 0.000 126.450 999.000 205.750 ;
    LAYER MET3 ;
    RECT 0.650 205.750 998.350 206.050 ;
    LAYER MET3 ;
    RECT 0.000 206.050 999.000 207.950 ;
    LAYER MET3 ;
    RECT 0.650 207.950 998.350 208.250 ;
    LAYER MET3 ;
    RECT 0.000 208.250 999.000 210.150 ;
    LAYER MET3 ;
    RECT 0.650 210.150 998.350 210.450 ;
    LAYER MET3 ;
    RECT 0.000 210.450 999.000 289.750 ;
    LAYER MET3 ;
    RECT 0.650 289.750 998.350 290.050 ;
    LAYER MET3 ;
    RECT 0.000 290.050 999.000 291.950 ;
    LAYER MET3 ;
    RECT 0.650 291.950 998.350 292.250 ;
    LAYER MET3 ;
    RECT 0.000 292.250 999.000 294.150 ;
    LAYER MET3 ;
    RECT 0.650 294.150 998.350 294.450 ;
    LAYER MET3 ;
    RECT 0.000 294.450 999.000 373.750 ;
    LAYER MET3 ;
    RECT 0.650 373.750 998.350 374.050 ;
    LAYER MET3 ;
    RECT 0.000 374.050 999.000 375.950 ;
    LAYER MET3 ;
    RECT 0.650 375.950 998.350 376.250 ;
    LAYER MET3 ;
    RECT 0.000 376.250 999.000 378.150 ;
    LAYER MET3 ;
    RECT 0.650 378.150 998.350 378.450 ;
    LAYER MET3 ;
    RECT 0.000 378.450 999.000 457.750 ;
    LAYER MET3 ;
    RECT 0.650 457.750 998.350 458.050 ;
    LAYER MET3 ;
    RECT 0.000 458.050 999.000 459.950 ;
    LAYER MET3 ;
    RECT 0.650 459.950 998.350 460.250 ;
    LAYER MET3 ;
    RECT 0.000 460.250 999.000 462.150 ;
    LAYER MET3 ;
    RECT 0.650 462.150 998.350 462.450 ;
    LAYER MET3 ;
    RECT 0.000 462.450 999.000 541.750 ;
    LAYER MET3 ;
    RECT 0.650 541.750 998.350 542.050 ;
    LAYER MET3 ;
    RECT 0.000 542.050 999.000 543.950 ;
    LAYER MET3 ;
    RECT 0.650 543.950 998.350 544.250 ;
    LAYER MET3 ;
    RECT 0.000 544.250 999.000 546.150 ;
    LAYER MET3 ;
    RECT 0.650 546.150 998.350 546.450 ;
    LAYER MET3 ;
    RECT 0.000 546.450 999.000 625.750 ;
    LAYER MET3 ;
    RECT 0.650 625.750 998.350 626.050 ;
    LAYER MET3 ;
    RECT 0.000 626.050 999.000 627.950 ;
    LAYER MET3 ;
    RECT 0.650 627.950 998.350 628.250 ;
    LAYER MET3 ;
    RECT 0.000 628.250 999.000 630.150 ;
    LAYER MET3 ;
    RECT 0.650 630.150 998.350 630.450 ;
    LAYER MET3 ;
    RECT 0.000 630.450 999.000 709.750 ;
    LAYER MET3 ;
    RECT 0.650 709.750 998.350 710.050 ;
    LAYER MET3 ;
    RECT 0.000 710.050 999.000 711.950 ;
    LAYER MET3 ;
    RECT 0.650 711.950 998.350 712.250 ;
    LAYER MET3 ;
    RECT 0.000 712.250 999.000 714.150 ;
    LAYER MET3 ;
    RECT 0.650 714.150 998.350 714.450 ;
    LAYER MET3 ;
    RECT 0.000 714.450 999.000 793.750 ;
    LAYER MET3 ;
    RECT 0.650 793.750 998.350 794.050 ;
    LAYER MET3 ;
    RECT 0.000 794.050 999.000 795.950 ;
    LAYER MET3 ;
    RECT 0.650 795.950 998.350 796.250 ;
    LAYER MET3 ;
    RECT 0.000 796.250 999.000 798.150 ;
    LAYER MET3 ;
    RECT 0.650 798.150 998.350 798.450 ;
    LAYER MET3 ;
    RECT 0.000 798.450 999.000 877.750 ;
    LAYER MET3 ;
    RECT 0.650 877.750 998.350 878.050 ;
    LAYER MET3 ;
    RECT 0.000 878.050 999.000 879.950 ;
    LAYER MET3 ;
    RECT 0.650 879.950 998.350 880.250 ;
    LAYER MET3 ;
    RECT 0.000 880.250 999.000 882.150 ;
    LAYER MET3 ;
    RECT 0.650 882.150 998.350 882.450 ;
    LAYER MET3 ;
    RECT 0.000 882.450 999.000 912.600 ;
    LAYER MET4 ;
    RECT 0.000 0.000 2.350 912.600 ;
    LAYER MET4 ;
    RECT 2.350 0.650 2.650 912.600 ;
    LAYER MET4 ;
    RECT 2.650 0.000 2.950 912.600 ;
    LAYER MET4 ;
    RECT 2.950 0.650 3.250 912.600 ;
    LAYER MET4 ;
    RECT 3.250 0.000 3.550 912.600 ;
    LAYER MET4 ;
    RECT 3.550 0.650 3.850 912.600 ;
    LAYER MET4 ;
    RECT 3.850 0.000 5.950 912.600 ;
    LAYER MET4 ;
    RECT 5.950 0.650 6.250 912.600 ;
    LAYER MET4 ;
    RECT 6.250 0.000 6.550 912.600 ;
    LAYER MET4 ;
    RECT 6.550 0.650 6.850 912.600 ;
    LAYER MET4 ;
    RECT 6.850 0.000 7.150 912.600 ;
    LAYER MET4 ;
    RECT 7.150 0.650 7.450 912.600 ;
    LAYER MET4 ;
    RECT 7.450 0.000 7.750 912.600 ;
    LAYER MET4 ;
    RECT 7.750 0.650 8.050 912.600 ;
    LAYER MET4 ;
    RECT 8.050 0.000 8.350 912.600 ;
    LAYER MET4 ;
    RECT 8.350 0.650 8.650 912.600 ;
    LAYER MET4 ;
    RECT 8.650 0.000 8.950 912.600 ;
    LAYER MET4 ;
    RECT 8.950 0.650 9.250 912.600 ;
    LAYER MET4 ;
    RECT 9.250 0.000 9.550 912.600 ;
    LAYER MET4 ;
    RECT 9.550 0.650 9.850 912.600 ;
    LAYER MET4 ;
    RECT 9.850 0.000 10.150 912.600 ;
    LAYER MET4 ;
    RECT 10.150 0.650 10.450 912.600 ;
    LAYER MET4 ;
    RECT 10.450 0.000 10.750 912.600 ;
    LAYER MET4 ;
    RECT 10.750 0.650 11.050 912.600 ;
    LAYER MET4 ;
    RECT 11.050 0.000 11.350 912.600 ;
    LAYER MET4 ;
    RECT 11.350 0.650 11.650 912.600 ;
    LAYER MET4 ;
    RECT 11.650 0.000 11.950 912.600 ;
    LAYER MET4 ;
    RECT 11.950 0.650 12.250 912.600 ;
    LAYER MET4 ;
    RECT 12.250 0.000 14.350 912.600 ;
    LAYER MET4 ;
    RECT 14.350 0.650 14.650 912.600 ;
    LAYER MET4 ;
    RECT 14.650 0.000 14.950 912.600 ;
    LAYER MET4 ;
    RECT 14.950 0.650 15.250 912.600 ;
    LAYER MET4 ;
    RECT 15.250 0.000 15.550 912.600 ;
    LAYER MET4 ;
    RECT 15.550 0.650 15.850 912.600 ;
    LAYER MET4 ;
    RECT 15.850 0.000 16.150 912.600 ;
    LAYER MET4 ;
    RECT 16.150 0.650 16.450 912.600 ;
    LAYER MET4 ;
    RECT 16.450 0.000 16.750 912.600 ;
    LAYER MET4 ;
    RECT 16.750 0.650 17.050 912.600 ;
    LAYER MET4 ;
    RECT 17.050 0.000 17.350 912.600 ;
    LAYER MET4 ;
    RECT 17.350 0.650 17.650 912.600 ;
    LAYER MET4 ;
    RECT 17.650 0.000 17.950 912.600 ;
    LAYER MET4 ;
    RECT 17.950 0.650 18.250 912.600 ;
    LAYER MET4 ;
    RECT 18.250 0.000 18.550 912.600 ;
    LAYER MET4 ;
    RECT 18.550 0.650 18.850 912.600 ;
    LAYER MET4 ;
    RECT 18.850 0.000 19.150 912.600 ;
    LAYER MET4 ;
    RECT 19.150 0.650 19.450 912.600 ;
    LAYER MET4 ;
    RECT 19.450 0.000 19.750 912.600 ;
    LAYER MET4 ;
    RECT 19.750 0.650 20.050 912.600 ;
    LAYER MET4 ;
    RECT 20.050 0.000 20.350 912.600 ;
    LAYER MET4 ;
    RECT 20.350 0.650 20.650 912.600 ;
    LAYER MET4 ;
    RECT 20.650 0.000 22.750 912.600 ;
    LAYER MET4 ;
    RECT 22.750 0.650 23.050 912.600 ;
    LAYER MET4 ;
    RECT 23.050 0.000 23.350 912.600 ;
    LAYER MET4 ;
    RECT 23.350 0.650 23.650 912.600 ;
    LAYER MET4 ;
    RECT 23.650 0.000 23.950 912.600 ;
    LAYER MET4 ;
    RECT 23.950 0.650 24.250 912.600 ;
    LAYER MET4 ;
    RECT 24.250 0.000 24.550 912.600 ;
    LAYER MET4 ;
    RECT 24.550 0.650 24.850 912.600 ;
    LAYER MET4 ;
    RECT 24.850 0.000 25.150 912.600 ;
    LAYER MET4 ;
    RECT 25.150 0.650 25.450 912.600 ;
    LAYER MET4 ;
    RECT 25.450 0.000 25.750 912.600 ;
    LAYER MET4 ;
    RECT 25.750 0.650 26.050 912.600 ;
    LAYER MET4 ;
    RECT 26.050 0.000 26.350 912.600 ;
    LAYER MET4 ;
    RECT 26.350 0.650 26.650 912.600 ;
    LAYER MET4 ;
    RECT 26.650 0.000 26.950 912.600 ;
    LAYER MET4 ;
    RECT 26.950 0.650 27.250 912.600 ;
    LAYER MET4 ;
    RECT 27.250 0.000 27.550 912.600 ;
    LAYER MET4 ;
    RECT 27.550 0.650 27.850 912.600 ;
    LAYER MET4 ;
    RECT 27.850 0.000 28.150 912.600 ;
    LAYER MET4 ;
    RECT 28.150 0.650 28.450 912.600 ;
    LAYER MET4 ;
    RECT 28.450 0.000 28.750 912.600 ;
    LAYER MET4 ;
    RECT 28.750 0.650 29.050 912.600 ;
    LAYER MET4 ;
    RECT 29.050 0.000 31.150 912.600 ;
    LAYER MET4 ;
    RECT 31.150 0.650 31.450 912.600 ;
    LAYER MET4 ;
    RECT 31.450 0.000 31.750 912.600 ;
    LAYER MET4 ;
    RECT 31.750 0.650 32.050 912.600 ;
    LAYER MET4 ;
    RECT 32.050 0.000 32.350 912.600 ;
    LAYER MET4 ;
    RECT 32.350 0.650 32.650 912.600 ;
    LAYER MET4 ;
    RECT 32.650 0.000 32.950 912.600 ;
    LAYER MET4 ;
    RECT 32.950 0.650 33.250 912.600 ;
    LAYER MET4 ;
    RECT 33.250 0.000 33.550 912.600 ;
    LAYER MET4 ;
    RECT 33.550 0.650 33.850 912.600 ;
    LAYER MET4 ;
    RECT 33.850 0.000 34.150 912.600 ;
    LAYER MET4 ;
    RECT 34.150 0.650 34.450 912.600 ;
    LAYER MET4 ;
    RECT 34.450 0.000 34.750 912.600 ;
    LAYER MET4 ;
    RECT 34.750 0.650 35.050 912.600 ;
    LAYER MET4 ;
    RECT 35.050 0.000 35.350 912.600 ;
    LAYER MET4 ;
    RECT 35.350 0.650 35.650 912.600 ;
    LAYER MET4 ;
    RECT 35.650 0.000 35.950 912.600 ;
    LAYER MET4 ;
    RECT 35.950 0.650 36.250 912.600 ;
    LAYER MET4 ;
    RECT 36.250 0.000 151.150 912.600 ;
    LAYER MET4 ;
    RECT 151.150 0.650 151.450 911.950 ;
    LAYER MET4 ;
    RECT 151.450 0.000 153.950 912.600 ;
    LAYER MET4 ;
    RECT 153.950 0.650 154.250 911.950 ;
    LAYER MET4 ;
    RECT 154.250 0.000 158.350 912.600 ;
    LAYER MET4 ;
    RECT 158.350 0.650 158.650 911.950 ;
    LAYER MET4 ;
    RECT 158.650 0.000 233.750 912.600 ;
    LAYER MET4 ;
    RECT 233.750 0.650 234.050 911.950 ;
    LAYER MET4 ;
    RECT 234.050 0.000 236.550 912.600 ;
    LAYER MET4 ;
    RECT 236.550 0.650 236.850 911.950 ;
    LAYER MET4 ;
    RECT 236.850 0.000 240.950 912.600 ;
    LAYER MET4 ;
    RECT 240.950 0.650 241.250 911.950 ;
    LAYER MET4 ;
    RECT 241.250 0.000 316.350 912.600 ;
    LAYER MET4 ;
    RECT 316.350 0.650 316.650 911.950 ;
    LAYER MET4 ;
    RECT 316.650 0.000 319.150 912.600 ;
    LAYER MET4 ;
    RECT 319.150 0.650 319.450 911.950 ;
    LAYER MET4 ;
    RECT 319.450 0.000 323.550 912.600 ;
    LAYER MET4 ;
    RECT 323.550 0.650 323.850 911.950 ;
    LAYER MET4 ;
    RECT 323.850 0.000 398.950 912.600 ;
    LAYER MET4 ;
    RECT 398.950 0.650 399.250 911.950 ;
    LAYER MET4 ;
    RECT 399.250 0.000 401.750 912.600 ;
    LAYER MET4 ;
    RECT 401.750 0.650 402.050 911.950 ;
    LAYER MET4 ;
    RECT 402.050 0.000 406.150 912.600 ;
    LAYER MET4 ;
    RECT 406.150 0.650 406.450 911.950 ;
    LAYER MET4 ;
    RECT 406.450 0.000 481.550 912.600 ;
    LAYER MET4 ;
    RECT 481.550 0.650 481.850 911.950 ;
    LAYER MET4 ;
    RECT 481.850 0.000 484.350 912.600 ;
    LAYER MET4 ;
    RECT 484.350 0.650 484.650 911.950 ;
    LAYER MET4 ;
    RECT 484.650 0.000 488.750 912.600 ;
    LAYER MET4 ;
    RECT 488.750 0.650 489.050 911.950 ;
    LAYER MET4 ;
    RECT 489.050 0.000 634.950 912.600 ;
    LAYER MET4 ;
    RECT 634.950 0.650 635.250 911.950 ;
    LAYER MET4 ;
    RECT 635.250 0.000 637.750 912.600 ;
    LAYER MET4 ;
    RECT 637.750 0.650 638.050 911.950 ;
    LAYER MET4 ;
    RECT 638.050 0.000 642.150 912.600 ;
    LAYER MET4 ;
    RECT 642.150 0.650 642.450 911.950 ;
    LAYER MET4 ;
    RECT 642.450 0.000 717.550 912.600 ;
    LAYER MET4 ;
    RECT 717.550 0.650 717.850 911.950 ;
    LAYER MET4 ;
    RECT 717.850 0.000 720.350 912.600 ;
    LAYER MET4 ;
    RECT 720.350 0.650 720.650 911.950 ;
    LAYER MET4 ;
    RECT 720.650 0.000 724.750 912.600 ;
    LAYER MET4 ;
    RECT 724.750 0.650 725.050 911.950 ;
    LAYER MET4 ;
    RECT 725.050 0.000 800.150 912.600 ;
    LAYER MET4 ;
    RECT 800.150 0.650 800.450 911.950 ;
    LAYER MET4 ;
    RECT 800.450 0.000 802.950 912.600 ;
    LAYER MET4 ;
    RECT 802.950 0.650 803.250 911.950 ;
    LAYER MET4 ;
    RECT 803.250 0.000 807.350 912.600 ;
    LAYER MET4 ;
    RECT 807.350 0.650 807.650 911.950 ;
    LAYER MET4 ;
    RECT 807.650 0.000 882.750 912.600 ;
    LAYER MET4 ;
    RECT 882.750 0.650 883.050 911.950 ;
    LAYER MET4 ;
    RECT 883.050 0.000 885.550 912.600 ;
    LAYER MET4 ;
    RECT 885.550 0.650 885.850 911.950 ;
    LAYER MET4 ;
    RECT 885.850 0.000 889.950 912.600 ;
    LAYER MET4 ;
    RECT 889.950 0.650 890.250 911.950 ;
    LAYER MET4 ;
    RECT 890.250 0.000 965.350 912.600 ;
    LAYER MET4 ;
    RECT 965.350 0.650 965.650 911.950 ;
    LAYER MET4 ;
    RECT 965.650 0.000 968.150 912.600 ;
    LAYER MET4 ;
    RECT 968.150 0.650 968.450 911.950 ;
    LAYER MET4 ;
    RECT 968.450 0.000 972.550 912.600 ;
    LAYER MET4 ;
    RECT 972.550 0.650 972.850 911.950 ;
    LAYER MET4 ;
    RECT 972.850 0.000 999.000 912.600 ;
    LAYER MET5 ;
    RECT 0.000 0.000 999.000 4.400 ;
    LAYER MET5 ;
    RECT 0.000 4.400 1.900 5.600 ;
    LAYER MET5 ;
    RECT 997.100 4.400 999.000 5.600 ;
    LAYER MET5 ;
    RECT 0.000 5.600 999.000 12.800 ;
    LAYER MET5 ;
    RECT 0.000 12.800 1.900 14.000 ;
    LAYER MET5 ;
    RECT 997.100 12.800 999.000 14.000 ;
    LAYER MET5 ;
    RECT 0.000 14.000 999.000 21.200 ;
    LAYER MET5 ;
    RECT 0.000 21.200 1.900 22.400 ;
    LAYER MET5 ;
    RECT 997.100 21.200 999.000 22.400 ;
    LAYER MET5 ;
    RECT 0.000 22.400 999.000 27.000 ;
    LAYER MET5 ;
    RECT 0.000 27.000 1.900 28.200 ;
    LAYER MET5 ;
    RECT 50.100 27.000 999.000 28.200 ;
    LAYER MET5 ;
    RECT 0.000 28.200 999.000 35.400 ;
    LAYER MET5 ;
    RECT 0.000 35.400 1.900 36.600 ;
    LAYER MET5 ;
    RECT 50.100 35.400 999.000 36.600 ;
    LAYER MET5 ;
    RECT 0.000 36.600 999.000 49.400 ;
    LAYER MET5 ;
    RECT 0.000 49.400 1.900 50.600 ;
    LAYER MET5 ;
    RECT 50.100 49.400 999.000 50.600 ;
    LAYER MET5 ;
    RECT 0.000 50.600 999.000 57.800 ;
    LAYER MET5 ;
    RECT 0.000 57.800 1.900 59.000 ;
    LAYER MET5 ;
    RECT 50.100 57.800 999.000 59.000 ;
    LAYER MET5 ;
    RECT 0.000 59.000 999.000 66.200 ;
    LAYER MET5 ;
    RECT 0.000 66.200 1.900 67.400 ;
    LAYER MET5 ;
    RECT 50.100 66.200 999.000 67.400 ;
    LAYER MET5 ;
    RECT 0.000 67.400 999.000 74.600 ;
    LAYER MET5 ;
    RECT 0.000 74.600 1.900 75.800 ;
    LAYER MET5 ;
    RECT 50.100 74.600 999.000 75.800 ;
    LAYER MET5 ;
    RECT 0.000 75.800 999.000 83.000 ;
    LAYER MET5 ;
    RECT 0.000 83.000 1.900 84.200 ;
    LAYER MET5 ;
    RECT 50.100 83.000 999.000 84.200 ;
    LAYER MET5 ;
    RECT 0.000 84.200 999.000 91.400 ;
    LAYER MET5 ;
    RECT 0.000 91.400 1.900 92.600 ;
    LAYER MET5 ;
    RECT 50.100 91.400 999.000 92.600 ;
    LAYER MET5 ;
    RECT 0.000 92.600 999.000 99.800 ;
    LAYER MET5 ;
    RECT 0.000 99.800 1.900 101.000 ;
    LAYER MET5 ;
    RECT 50.100 99.800 999.000 101.000 ;
    LAYER MET5 ;
    RECT 0.000 101.000 999.000 108.200 ;
    LAYER MET5 ;
    RECT 0.000 108.200 1.900 109.400 ;
    LAYER MET5 ;
    RECT 50.100 108.200 999.000 109.400 ;
    LAYER MET5 ;
    RECT 0.000 109.400 999.000 116.600 ;
    LAYER MET5 ;
    RECT 0.000 116.600 1.900 117.800 ;
    LAYER MET5 ;
    RECT 50.100 116.600 999.000 117.800 ;
    LAYER MET5 ;
    RECT 0.000 117.800 999.000 125.000 ;
    LAYER MET5 ;
    RECT 0.000 125.000 1.900 126.200 ;
    LAYER MET5 ;
    RECT 50.100 125.000 999.000 126.200 ;
    LAYER MET5 ;
    RECT 0.000 126.200 999.000 133.400 ;
    LAYER MET5 ;
    RECT 0.000 133.400 1.900 134.600 ;
    LAYER MET5 ;
    RECT 50.100 133.400 999.000 134.600 ;
    LAYER MET5 ;
    RECT 0.000 134.600 999.000 141.800 ;
    LAYER MET5 ;
    RECT 0.000 141.800 1.900 143.000 ;
    LAYER MET5 ;
    RECT 50.100 141.800 999.000 143.000 ;
    LAYER MET5 ;
    RECT 0.000 143.000 999.000 150.200 ;
    LAYER MET5 ;
    RECT 0.000 150.200 1.900 151.400 ;
    LAYER MET5 ;
    RECT 50.100 150.200 999.000 151.400 ;
    LAYER MET5 ;
    RECT 0.000 151.400 999.000 158.600 ;
    LAYER MET5 ;
    RECT 0.000 158.600 1.900 159.800 ;
    LAYER MET5 ;
    RECT 50.100 158.600 999.000 159.800 ;
    LAYER MET5 ;
    RECT 0.000 159.800 999.000 167.000 ;
    LAYER MET5 ;
    RECT 0.000 167.000 1.900 168.200 ;
    LAYER MET5 ;
    RECT 50.100 167.000 999.000 168.200 ;
    LAYER MET5 ;
    RECT 0.000 168.200 999.000 175.400 ;
    LAYER MET5 ;
    RECT 0.000 175.400 1.900 176.600 ;
    LAYER MET5 ;
    RECT 50.100 175.400 999.000 176.600 ;
    LAYER MET5 ;
    RECT 0.000 176.600 999.000 183.800 ;
    LAYER MET5 ;
    RECT 0.000 183.800 1.900 185.000 ;
    LAYER MET5 ;
    RECT 50.100 183.800 999.000 185.000 ;
    LAYER MET5 ;
    RECT 0.000 185.000 999.000 192.200 ;
    LAYER MET5 ;
    RECT 0.000 192.200 1.900 193.400 ;
    LAYER MET5 ;
    RECT 50.100 192.200 999.000 193.400 ;
    LAYER MET5 ;
    RECT 0.000 193.400 999.000 200.600 ;
    LAYER MET5 ;
    RECT 0.000 200.600 1.900 201.800 ;
    LAYER MET5 ;
    RECT 50.100 200.600 999.000 201.800 ;
    LAYER MET5 ;
    RECT 0.000 201.800 999.000 209.000 ;
    LAYER MET5 ;
    RECT 0.000 209.000 1.900 210.200 ;
    LAYER MET5 ;
    RECT 50.100 209.000 999.000 210.200 ;
    LAYER MET5 ;
    RECT 0.000 210.200 999.000 217.400 ;
    LAYER MET5 ;
    RECT 0.000 217.400 1.900 218.600 ;
    LAYER MET5 ;
    RECT 50.100 217.400 999.000 218.600 ;
    LAYER MET5 ;
    RECT 0.000 218.600 999.000 225.800 ;
    LAYER MET5 ;
    RECT 0.000 225.800 1.900 227.000 ;
    LAYER MET5 ;
    RECT 50.100 225.800 999.000 227.000 ;
    LAYER MET5 ;
    RECT 0.000 227.000 999.000 234.200 ;
    LAYER MET5 ;
    RECT 0.000 234.200 1.900 235.400 ;
    LAYER MET5 ;
    RECT 50.100 234.200 999.000 235.400 ;
    LAYER MET5 ;
    RECT 0.000 235.400 999.000 242.600 ;
    LAYER MET5 ;
    RECT 0.000 242.600 1.900 243.800 ;
    LAYER MET5 ;
    RECT 50.100 242.600 999.000 243.800 ;
    LAYER MET5 ;
    RECT 0.000 243.800 999.000 251.000 ;
    LAYER MET5 ;
    RECT 0.000 251.000 1.900 252.200 ;
    LAYER MET5 ;
    RECT 50.100 251.000 999.000 252.200 ;
    LAYER MET5 ;
    RECT 0.000 252.200 999.000 259.400 ;
    LAYER MET5 ;
    RECT 0.000 259.400 1.900 260.600 ;
    LAYER MET5 ;
    RECT 50.100 259.400 999.000 260.600 ;
    LAYER MET5 ;
    RECT 0.000 260.600 999.000 267.800 ;
    LAYER MET5 ;
    RECT 0.000 267.800 1.900 269.000 ;
    LAYER MET5 ;
    RECT 50.100 267.800 999.000 269.000 ;
    LAYER MET5 ;
    RECT 0.000 269.000 999.000 276.200 ;
    LAYER MET5 ;
    RECT 0.000 276.200 1.900 277.400 ;
    LAYER MET5 ;
    RECT 50.100 276.200 999.000 277.400 ;
    LAYER MET5 ;
    RECT 0.000 277.400 999.000 284.600 ;
    LAYER MET5 ;
    RECT 0.000 284.600 1.900 285.800 ;
    LAYER MET5 ;
    RECT 50.100 284.600 999.000 285.800 ;
    LAYER MET5 ;
    RECT 0.000 285.800 999.000 293.000 ;
    LAYER MET5 ;
    RECT 0.000 293.000 1.900 294.200 ;
    LAYER MET5 ;
    RECT 50.100 293.000 999.000 294.200 ;
    LAYER MET5 ;
    RECT 0.000 294.200 999.000 301.400 ;
    LAYER MET5 ;
    RECT 0.000 301.400 1.900 302.600 ;
    LAYER MET5 ;
    RECT 50.100 301.400 999.000 302.600 ;
    LAYER MET5 ;
    RECT 0.000 302.600 999.000 309.800 ;
    LAYER MET5 ;
    RECT 0.000 309.800 1.900 311.000 ;
    LAYER MET5 ;
    RECT 50.100 309.800 999.000 311.000 ;
    LAYER MET5 ;
    RECT 0.000 311.000 999.000 318.200 ;
    LAYER MET5 ;
    RECT 0.000 318.200 1.900 319.400 ;
    LAYER MET5 ;
    RECT 50.100 318.200 999.000 319.400 ;
    LAYER MET5 ;
    RECT 0.000 319.400 999.000 326.600 ;
    LAYER MET5 ;
    RECT 0.000 326.600 1.900 327.800 ;
    LAYER MET5 ;
    RECT 50.100 326.600 999.000 327.800 ;
    LAYER MET5 ;
    RECT 0.000 327.800 999.000 335.000 ;
    LAYER MET5 ;
    RECT 0.000 335.000 1.900 336.200 ;
    LAYER MET5 ;
    RECT 50.100 335.000 999.000 336.200 ;
    LAYER MET5 ;
    RECT 0.000 336.200 999.000 343.400 ;
    LAYER MET5 ;
    RECT 0.000 343.400 1.900 344.600 ;
    LAYER MET5 ;
    RECT 50.100 343.400 999.000 344.600 ;
    LAYER MET5 ;
    RECT 0.000 344.600 999.000 351.800 ;
    LAYER MET5 ;
    RECT 0.000 351.800 1.900 353.000 ;
    LAYER MET5 ;
    RECT 50.100 351.800 999.000 353.000 ;
    LAYER MET5 ;
    RECT 0.000 353.000 999.000 360.200 ;
    LAYER MET5 ;
    RECT 0.000 360.200 1.900 361.400 ;
    LAYER MET5 ;
    RECT 50.100 360.200 999.000 361.400 ;
    LAYER MET5 ;
    RECT 0.000 361.400 999.000 368.600 ;
    LAYER MET5 ;
    RECT 0.000 368.600 1.900 369.800 ;
    LAYER MET5 ;
    RECT 50.100 368.600 999.000 369.800 ;
    LAYER MET5 ;
    RECT 0.000 369.800 999.000 377.000 ;
    LAYER MET5 ;
    RECT 0.000 377.000 1.900 378.200 ;
    LAYER MET5 ;
    RECT 50.100 377.000 999.000 378.200 ;
    LAYER MET5 ;
    RECT 0.000 378.200 999.000 385.400 ;
    LAYER MET5 ;
    RECT 0.000 385.400 1.900 386.600 ;
    LAYER MET5 ;
    RECT 50.100 385.400 999.000 386.600 ;
    LAYER MET5 ;
    RECT 0.000 386.600 999.000 393.800 ;
    LAYER MET5 ;
    RECT 0.000 393.800 1.900 395.000 ;
    LAYER MET5 ;
    RECT 50.100 393.800 999.000 395.000 ;
    LAYER MET5 ;
    RECT 0.000 395.000 999.000 402.200 ;
    LAYER MET5 ;
    RECT 0.000 402.200 1.900 403.400 ;
    LAYER MET5 ;
    RECT 50.100 402.200 999.000 403.400 ;
    LAYER MET5 ;
    RECT 0.000 403.400 999.000 410.600 ;
    LAYER MET5 ;
    RECT 0.000 410.600 1.900 411.800 ;
    LAYER MET5 ;
    RECT 50.100 410.600 999.000 411.800 ;
    LAYER MET5 ;
    RECT 0.000 411.800 999.000 419.000 ;
    LAYER MET5 ;
    RECT 0.000 419.000 1.900 420.200 ;
    LAYER MET5 ;
    RECT 50.100 419.000 999.000 420.200 ;
    LAYER MET5 ;
    RECT 0.000 420.200 999.000 427.400 ;
    LAYER MET5 ;
    RECT 0.000 427.400 1.900 428.600 ;
    LAYER MET5 ;
    RECT 50.100 427.400 999.000 428.600 ;
    LAYER MET5 ;
    RECT 0.000 428.600 999.000 435.800 ;
    LAYER MET5 ;
    RECT 0.000 435.800 1.900 437.000 ;
    LAYER MET5 ;
    RECT 50.100 435.800 999.000 437.000 ;
    LAYER MET5 ;
    RECT 0.000 437.000 999.000 444.200 ;
    LAYER MET5 ;
    RECT 0.000 444.200 1.900 445.400 ;
    LAYER MET5 ;
    RECT 50.100 444.200 999.000 445.400 ;
    LAYER MET5 ;
    RECT 0.000 445.400 999.000 452.600 ;
    LAYER MET5 ;
    RECT 0.000 452.600 1.900 453.800 ;
    LAYER MET5 ;
    RECT 50.100 452.600 999.000 453.800 ;
    LAYER MET5 ;
    RECT 0.000 453.800 999.000 461.000 ;
    LAYER MET5 ;
    RECT 0.000 461.000 1.900 462.200 ;
    LAYER MET5 ;
    RECT 50.100 461.000 999.000 462.200 ;
    LAYER MET5 ;
    RECT 0.000 462.200 999.000 469.400 ;
    LAYER MET5 ;
    RECT 0.000 469.400 1.900 470.600 ;
    LAYER MET5 ;
    RECT 50.100 469.400 999.000 470.600 ;
    LAYER MET5 ;
    RECT 0.000 470.600 999.000 477.800 ;
    LAYER MET5 ;
    RECT 0.000 477.800 1.900 479.000 ;
    LAYER MET5 ;
    RECT 50.100 477.800 999.000 479.000 ;
    LAYER MET5 ;
    RECT 0.000 479.000 999.000 486.200 ;
    LAYER MET5 ;
    RECT 0.000 486.200 1.900 487.400 ;
    LAYER MET5 ;
    RECT 50.100 486.200 999.000 487.400 ;
    LAYER MET5 ;
    RECT 0.000 487.400 999.000 494.600 ;
    LAYER MET5 ;
    RECT 0.000 494.600 1.900 495.800 ;
    LAYER MET5 ;
    RECT 50.100 494.600 999.000 495.800 ;
    LAYER MET5 ;
    RECT 0.000 495.800 999.000 503.000 ;
    LAYER MET5 ;
    RECT 0.000 503.000 1.900 504.200 ;
    LAYER MET5 ;
    RECT 50.100 503.000 999.000 504.200 ;
    LAYER MET5 ;
    RECT 0.000 504.200 999.000 511.400 ;
    LAYER MET5 ;
    RECT 0.000 511.400 1.900 512.600 ;
    LAYER MET5 ;
    RECT 50.100 511.400 999.000 512.600 ;
    LAYER MET5 ;
    RECT 0.000 512.600 999.000 519.800 ;
    LAYER MET5 ;
    RECT 0.000 519.800 1.900 521.000 ;
    LAYER MET5 ;
    RECT 50.100 519.800 999.000 521.000 ;
    LAYER MET5 ;
    RECT 0.000 521.000 999.000 528.200 ;
    LAYER MET5 ;
    RECT 0.000 528.200 1.900 529.400 ;
    LAYER MET5 ;
    RECT 50.100 528.200 999.000 529.400 ;
    LAYER MET5 ;
    RECT 0.000 529.400 999.000 536.600 ;
    LAYER MET5 ;
    RECT 0.000 536.600 1.900 537.800 ;
    LAYER MET5 ;
    RECT 50.100 536.600 999.000 537.800 ;
    LAYER MET5 ;
    RECT 0.000 537.800 999.000 545.000 ;
    LAYER MET5 ;
    RECT 0.000 545.000 1.900 546.200 ;
    LAYER MET5 ;
    RECT 50.100 545.000 999.000 546.200 ;
    LAYER MET5 ;
    RECT 0.000 546.200 999.000 553.400 ;
    LAYER MET5 ;
    RECT 0.000 553.400 1.900 554.600 ;
    LAYER MET5 ;
    RECT 50.100 553.400 999.000 554.600 ;
    LAYER MET5 ;
    RECT 0.000 554.600 999.000 561.800 ;
    LAYER MET5 ;
    RECT 0.000 561.800 1.900 563.000 ;
    LAYER MET5 ;
    RECT 50.100 561.800 999.000 563.000 ;
    LAYER MET5 ;
    RECT 0.000 563.000 999.000 570.200 ;
    LAYER MET5 ;
    RECT 0.000 570.200 1.900 571.400 ;
    LAYER MET5 ;
    RECT 50.100 570.200 999.000 571.400 ;
    LAYER MET5 ;
    RECT 0.000 571.400 999.000 578.600 ;
    LAYER MET5 ;
    RECT 0.000 578.600 1.900 579.800 ;
    LAYER MET5 ;
    RECT 50.100 578.600 999.000 579.800 ;
    LAYER MET5 ;
    RECT 0.000 579.800 999.000 587.000 ;
    LAYER MET5 ;
    RECT 0.000 587.000 1.900 588.200 ;
    LAYER MET5 ;
    RECT 50.100 587.000 999.000 588.200 ;
    LAYER MET5 ;
    RECT 0.000 588.200 999.000 595.400 ;
    LAYER MET5 ;
    RECT 0.000 595.400 1.900 596.600 ;
    LAYER MET5 ;
    RECT 50.100 595.400 999.000 596.600 ;
    LAYER MET5 ;
    RECT 0.000 596.600 999.000 603.800 ;
    LAYER MET5 ;
    RECT 0.000 603.800 1.900 605.000 ;
    LAYER MET5 ;
    RECT 50.100 603.800 999.000 605.000 ;
    LAYER MET5 ;
    RECT 0.000 605.000 999.000 612.200 ;
    LAYER MET5 ;
    RECT 0.000 612.200 1.900 613.400 ;
    LAYER MET5 ;
    RECT 50.100 612.200 999.000 613.400 ;
    LAYER MET5 ;
    RECT 0.000 613.400 999.000 620.600 ;
    LAYER MET5 ;
    RECT 0.000 620.600 1.900 621.800 ;
    LAYER MET5 ;
    RECT 50.100 620.600 999.000 621.800 ;
    LAYER MET5 ;
    RECT 0.000 621.800 999.000 629.000 ;
    LAYER MET5 ;
    RECT 0.000 629.000 1.900 630.200 ;
    LAYER MET5 ;
    RECT 50.100 629.000 999.000 630.200 ;
    LAYER MET5 ;
    RECT 0.000 630.200 999.000 637.400 ;
    LAYER MET5 ;
    RECT 0.000 637.400 1.900 638.600 ;
    LAYER MET5 ;
    RECT 50.100 637.400 999.000 638.600 ;
    LAYER MET5 ;
    RECT 0.000 638.600 999.000 645.800 ;
    LAYER MET5 ;
    RECT 0.000 645.800 1.900 647.000 ;
    LAYER MET5 ;
    RECT 50.100 645.800 999.000 647.000 ;
    LAYER MET5 ;
    RECT 0.000 647.000 999.000 654.200 ;
    LAYER MET5 ;
    RECT 0.000 654.200 1.900 655.400 ;
    LAYER MET5 ;
    RECT 50.100 654.200 999.000 655.400 ;
    LAYER MET5 ;
    RECT 0.000 655.400 999.000 662.600 ;
    LAYER MET5 ;
    RECT 0.000 662.600 1.900 663.800 ;
    LAYER MET5 ;
    RECT 50.100 662.600 999.000 663.800 ;
    LAYER MET5 ;
    RECT 0.000 663.800 999.000 671.000 ;
    LAYER MET5 ;
    RECT 0.000 671.000 1.900 672.200 ;
    LAYER MET5 ;
    RECT 50.100 671.000 999.000 672.200 ;
    LAYER MET5 ;
    RECT 0.000 672.200 999.000 679.400 ;
    LAYER MET5 ;
    RECT 0.000 679.400 1.900 680.600 ;
    LAYER MET5 ;
    RECT 50.100 679.400 999.000 680.600 ;
    LAYER MET5 ;
    RECT 0.000 680.600 999.000 687.800 ;
    LAYER MET5 ;
    RECT 0.000 687.800 1.900 689.000 ;
    LAYER MET5 ;
    RECT 50.100 687.800 999.000 689.000 ;
    LAYER MET5 ;
    RECT 0.000 689.000 999.000 696.200 ;
    LAYER MET5 ;
    RECT 0.000 696.200 1.900 697.400 ;
    LAYER MET5 ;
    RECT 50.100 696.200 999.000 697.400 ;
    LAYER MET5 ;
    RECT 0.000 697.400 999.000 704.600 ;
    LAYER MET5 ;
    RECT 0.000 704.600 1.900 705.800 ;
    LAYER MET5 ;
    RECT 50.100 704.600 999.000 705.800 ;
    LAYER MET5 ;
    RECT 0.000 705.800 999.000 713.000 ;
    LAYER MET5 ;
    RECT 0.000 713.000 1.900 714.200 ;
    LAYER MET5 ;
    RECT 50.100 713.000 999.000 714.200 ;
    LAYER MET5 ;
    RECT 0.000 714.200 999.000 721.400 ;
    LAYER MET5 ;
    RECT 0.000 721.400 1.900 722.600 ;
    LAYER MET5 ;
    RECT 50.100 721.400 999.000 722.600 ;
    LAYER MET5 ;
    RECT 0.000 722.600 999.000 729.800 ;
    LAYER MET5 ;
    RECT 0.000 729.800 1.900 731.000 ;
    LAYER MET5 ;
    RECT 50.100 729.800 999.000 731.000 ;
    LAYER MET5 ;
    RECT 0.000 731.000 999.000 738.200 ;
    LAYER MET5 ;
    RECT 0.000 738.200 1.900 739.400 ;
    LAYER MET5 ;
    RECT 50.100 738.200 999.000 739.400 ;
    LAYER MET5 ;
    RECT 0.000 739.400 999.000 746.600 ;
    LAYER MET5 ;
    RECT 0.000 746.600 1.900 747.800 ;
    LAYER MET5 ;
    RECT 50.100 746.600 999.000 747.800 ;
    LAYER MET5 ;
    RECT 0.000 747.800 999.000 755.000 ;
    LAYER MET5 ;
    RECT 0.000 755.000 1.900 756.200 ;
    LAYER MET5 ;
    RECT 50.100 755.000 999.000 756.200 ;
    LAYER MET5 ;
    RECT 0.000 756.200 999.000 763.400 ;
    LAYER MET5 ;
    RECT 0.000 763.400 1.900 764.600 ;
    LAYER MET5 ;
    RECT 50.100 763.400 999.000 764.600 ;
    LAYER MET5 ;
    RECT 0.000 764.600 999.000 771.800 ;
    LAYER MET5 ;
    RECT 0.000 771.800 1.900 773.000 ;
    LAYER MET5 ;
    RECT 50.100 771.800 999.000 773.000 ;
    LAYER MET5 ;
    RECT 0.000 773.000 999.000 780.200 ;
    LAYER MET5 ;
    RECT 0.000 780.200 1.900 781.400 ;
    LAYER MET5 ;
    RECT 50.100 780.200 999.000 781.400 ;
    LAYER MET5 ;
    RECT 0.000 781.400 999.000 788.600 ;
    LAYER MET5 ;
    RECT 0.000 788.600 1.900 789.800 ;
    LAYER MET5 ;
    RECT 50.100 788.600 999.000 789.800 ;
    LAYER MET5 ;
    RECT 0.000 789.800 999.000 797.000 ;
    LAYER MET5 ;
    RECT 0.000 797.000 1.900 798.200 ;
    LAYER MET5 ;
    RECT 50.100 797.000 999.000 798.200 ;
    LAYER MET5 ;
    RECT 0.000 798.200 999.000 805.400 ;
    LAYER MET5 ;
    RECT 0.000 805.400 1.900 806.600 ;
    LAYER MET5 ;
    RECT 50.100 805.400 999.000 806.600 ;
    LAYER MET5 ;
    RECT 0.000 806.600 999.000 813.800 ;
    LAYER MET5 ;
    RECT 0.000 813.800 1.900 815.000 ;
    LAYER MET5 ;
    RECT 50.100 813.800 999.000 815.000 ;
    LAYER MET5 ;
    RECT 0.000 815.000 999.000 822.200 ;
    LAYER MET5 ;
    RECT 0.000 822.200 1.900 823.400 ;
    LAYER MET5 ;
    RECT 50.100 822.200 999.000 823.400 ;
    LAYER MET5 ;
    RECT 0.000 823.400 999.000 830.600 ;
    LAYER MET5 ;
    RECT 0.000 830.600 1.900 831.800 ;
    LAYER MET5 ;
    RECT 50.100 830.600 999.000 831.800 ;
    LAYER MET5 ;
    RECT 0.000 831.800 999.000 839.000 ;
    LAYER MET5 ;
    RECT 0.000 839.000 1.900 840.200 ;
    LAYER MET5 ;
    RECT 50.100 839.000 999.000 840.200 ;
    LAYER MET5 ;
    RECT 0.000 840.200 999.000 847.400 ;
    LAYER MET5 ;
    RECT 0.000 847.400 1.900 848.600 ;
    LAYER MET5 ;
    RECT 50.100 847.400 999.000 848.600 ;
    LAYER MET5 ;
    RECT 0.000 848.600 999.000 855.800 ;
    LAYER MET5 ;
    RECT 0.000 855.800 1.900 857.000 ;
    LAYER MET5 ;
    RECT 50.100 855.800 999.000 857.000 ;
    LAYER MET5 ;
    RECT 0.000 857.000 999.000 864.200 ;
    LAYER MET5 ;
    RECT 0.000 864.200 1.900 865.400 ;
    LAYER MET5 ;
    RECT 50.100 864.200 999.000 865.400 ;
    LAYER MET5 ;
    RECT 0.000 865.400 999.000 872.600 ;
    LAYER MET5 ;
    RECT 0.000 872.600 1.900 873.800 ;
    LAYER MET5 ;
    RECT 50.100 872.600 999.000 873.800 ;
    LAYER MET5 ;
    RECT 0.000 873.800 999.000 881.000 ;
    LAYER MET5 ;
    RECT 0.000 881.000 1.900 882.200 ;
    LAYER MET5 ;
    RECT 50.100 881.000 999.000 882.200 ;
    LAYER MET5 ;
    RECT 0.000 882.200 999.000 889.400 ;
    LAYER MET5 ;
    RECT 0.000 889.400 1.900 890.600 ;
    LAYER MET5 ;
    RECT 50.100 889.400 999.000 890.600 ;
    LAYER MET5 ;
    RECT 0.000 890.600 999.000 897.800 ;
    LAYER MET5 ;
    RECT 0.000 897.800 1.900 899.000 ;
    LAYER MET5 ;
    RECT 50.100 897.800 999.000 899.000 ;
    LAYER MET5 ;
    RECT 0.000 899.000 999.000 912.600 ;
  END

END eFPGA_top

END LIBRARY
